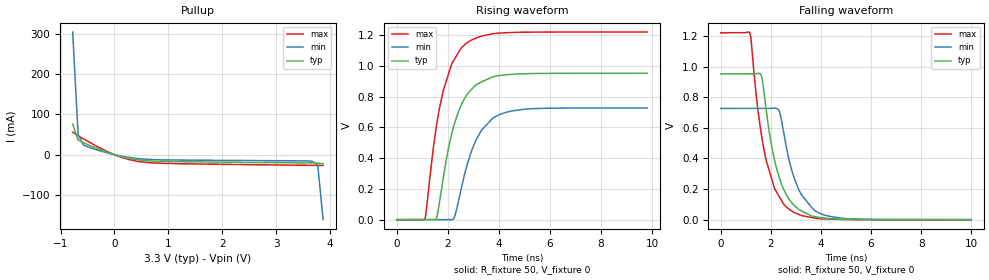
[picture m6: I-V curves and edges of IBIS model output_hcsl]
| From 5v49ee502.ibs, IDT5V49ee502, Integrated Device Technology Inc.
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[Model]   output_hcsl
Model_type   Open_source
Polarity   Non-Inverting
|   typ   min   max
C_comp   2pF   1.5pF   2.5pF
Vmeas = 0.475V
Rref = 50
Cref = 0
Vref = 0V
|   typ   min   max
[Voltage range]   3.3V   3.135V   3.465V
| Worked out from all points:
|   slope of the pullup table from 0 to 0.495 V, typ, clamps not added: 36.2 ohm
|   rising waveform, R_fixture 50, V_fixture 0: 20-80 % time 825ps typ, 869ps min, 802ps max; typ from 0 V to 0.952 V
|   falling waveform, R_fixture 50, V_fixture 0: 20-80 % time 756ps typ, 809ps min, 757ps max; typ from 0.952 V to 0 V
[Pullup]
|Voltage   I (typ)   I (min)   I (max)
|Note, modeling breaks down at 250mA and above.  This is well beyond the functional   |
|operating range of the device.  Should this scenario occur, catastrophic failure and   |
|possible damage to the device and/or board is of higher concern than the I-V curve   |
|behavior.  The IBIS checker will flag currents in excess of 10A with warnings.  Lines   |
|with currents in excess of 0.35 A have been commented out.  The points still remain|
|available to the user if the user desires to use them.   |
|-3.30000e+00   3.30638e+01   2.68010e+01   4.09657e+01
|-3.19898e+00   3.16603e+01   2.56927e+01   3.91797e+01
|-3.09796e+00   3.02576e+01   2.45850e+01   3.73944e+01
|-2.99694e+00   2.88557e+01   2.34780e+01   3.56099e+01
|-2.89592e+00   2.74545e+01   2.23718e+01   3.38263e+01
|-2.79490e+00   2.60544e+01   2.12664e+01   3.20438e+01
|-2.69388e+00   2.46552e+01   2.01619e+01   3.02623e+01
|-2.59286e+00   2.32572e+01   1.90584e+01   2.84820e+01
|-2.49184e+00   2.18605e+01   1.79561e+01   2.67032e+01
|-2.39082e+00   2.04653e+01   1.68551e+01   2.49259e+01
|-2.28980e+00   1.90717e+01   1.57554e+01   2.31504e+01
|-2.18878e+00   1.76800e+01   1.46575e+01   2.13771e+01
|-2.08776e+00   1.62905e+01   1.35614e+01   1.96061e+01
|-1.98673e+00   1.49036e+01   1.24675e+01   1.78381e+01
|-1.88571e+00   1.35198e+01   1.13762e+01   1.60736e+01
|-1.78469e+00   1.21397e+01   1.02880e+01   1.43133e+01
|-1.68367e+00   1.07642e+01   9.20353e+00   1.25584e+01
|-1.58265e+00   9.39447e+00   8.12370e+00   1.08104e+01
|-1.48163e+00   8.03224e+00   7.04975e+00   9.07171e+00
|-1.38061e+00   6.68011e+00   5.98351e+00   7.34597e+00
|-1.27959e+00   5.34234e+00   4.92772e+00   5.63973e+00
|-1.17857e+00   4.02639e+00   3.88695e+00   3.96580e+00
|-1.07755e+00   2.74730e+00   2.86935e+00   2.35494e+00
|-9.76531e-01   1.54173e+00   1.89160e+00   9.10722e-01
|-8.75510e-01   5.30047e-01   9.94813e-01   1.14991e-01
-774.5mV  75.97mA    304.6mA    55.9mA
-673.5mV  36.54mA    49.92mA    47.19mA
-572.4mV  29.57mA    23.79mA    39.18mA
-269.4mV  12.55mA    9.581mA    16.85mA
33.67mV   -1.332mA   -1.006mA   -1.807mA
235.7mV   -8.073mA   -6.115mA   -10.81mA
538.8mV   -14.28mA   -10.89mA   -18.63mA
1.246V    -17.55mA   -13.41mA   -22.54mA
3.67V     -20.48mA   -16.38mA   -26.54mA
3.771V    -20.93mA   -25.11mA   -26.7mA
3.872V    -22.81mA   -161.4mA   -27.04mA
| 3.97347e+00   -2.79466e-02   -1.04304e+00   -2.88374e-02
| 4.07449e+00   -6.78709e-02   -2.66934e+00   -3.44018e-02
| 4.17551e+00   -7.30752e-01   -4.58651e+00   -4.33487e-02
| 4.27653e+00   -2.68539e+00   -6.62766e+00   -5.68464e-02
| 4.37755e+00   -5.16352e+00   -8.73431e+00   -3.27836e-01
| 4.47857e+00   -7.82651e+00   -1.08809e+01   -2.58251e+00
| 4.57959e+00   -1.05777e+01   -1.30540e+01   -6.00804e+00
| 4.68061e+00   -1.33796e+01   -1.52462e+01   -9.74126e+00
| 4.78163e+00   -1.62143e+01   -1.74525e+01   -1.35998e+01
| 4.88265e+00   -1.90717e+01   -1.96699e+01   -1.75251e+01
| 4.98367e+00   -2.19459e+01   -2.18959e+01   -2.14915e+01
| 5.08469e+00   -2.48328e+01   -2.41291e+01   -2.54857e+01
| 5.18571e+00   -2.77298e+01   -2.63682e+01   -2.95000e+01
| 5.28673e+00   -3.06350e+01   -2.86123e+01   -3.35293e+01
| 5.38776e+00   -3.35469e+01   -3.08606e+01   -3.75704e+01
| 5.48878e+00   -3.64644e+01   -3.31126e+01   -4.16209e+01
| 5.58980e+00   -3.93867e+01   -3.53678e+01   -4.56791e+01
| 5.69082e+00   -4.23132e+01   -3.76258e+01   -4.97438e+01
| 5.79184e+00   -4.52432e+01   -3.98863e+01   -5.38139e+01
| 5.89286e+00   -4.81763e+01   -4.21491e+01   -5.78887e+01
| 5.99388e+00   -5.11123e+01   -4.44138e+01   -6.19676e+01
| 6.09490e+00   -5.40507e+01   -4.66804e+01   -6.60500e+01
| 6.19592e+00   -5.69914e+01   -4.89486e+01   -7.01355e+01
| 6.29694e+00   -5.99340e+01   -5.12183e+01   -7.42237e+01
| 6.39796e+00   -6.28785e+01   -5.34893e+01   -7.83145e+01
| 6.49898e+00   -6.58246e+01   -5.57616e+01   -8.24075e+01
| 6.60000e+00   -6.87722e+01   -5.80351e+01   -8.65025e+01
[Ramp]
|   typ   min   max
dV/dt_r   0.571/0.824n   0.435/0.868n   0.732/0.802n
dV/dt_f   0.573/0.755n   0.436/0.808n   0.735/0.757n
R_load =   50.0000
[Rising Waveform]
R_fixture = 50
V_fixture = 0   |Vcc_typ
V_fixture_min = 0 |Vcc_min
V_fixture_max = 0 |Vcc_max
C_fixture = 0.0p
| Time   typ   min   max
0s        193.5nV    161.3nV    244.3nV
1.101ns   171nV      160.8nV    5.079mV
1.551ns   6.706mV    153.6nV    604.4mV
1.807ns   255.1mV    387.4nV    829.7mV
2.027ns   465mV      -11.01uV   946.7mV
2.258ns   622.3mV    14.8mV     1.042V
2.742ns   809.7mV    348.2mV    1.148V
3.324ns   896.1mV    582.3mV    1.193V
4.256ns   941.6mV    696.6mV    1.215V
9.807ns   951.7mV    726.2mV    1.22V
[Falling Waveform]
R_fixture = 50
V_fixture = 0   |Vcc_typ
V_fixture_min = 0 |Vcc_min
V_fixture_max = 0 |Vcc_max
C_fixture = 0.0p
| Time   typ   min   max
0s        951.9mV    726.3mV    1.22V
1.156ns   951.9mV    726.3mV    1.22V
1.616ns   942.8mV    726.3mV    560.7mV
1.81ns    719.4mV    726.3mV    388.6mV
2.05ns    465.3mV    727mV      256.9mV
2.343ns   274.4mV    706mV      147.7mV
2.718ns   136.2mV    396.7mV    69.55mV
3.225ns   57.13mV    162.3mV    27.1mV
4.193ns   9.454mV    27.72mV    4.746mV
10ns      240.7uV    324uV      187.2uV
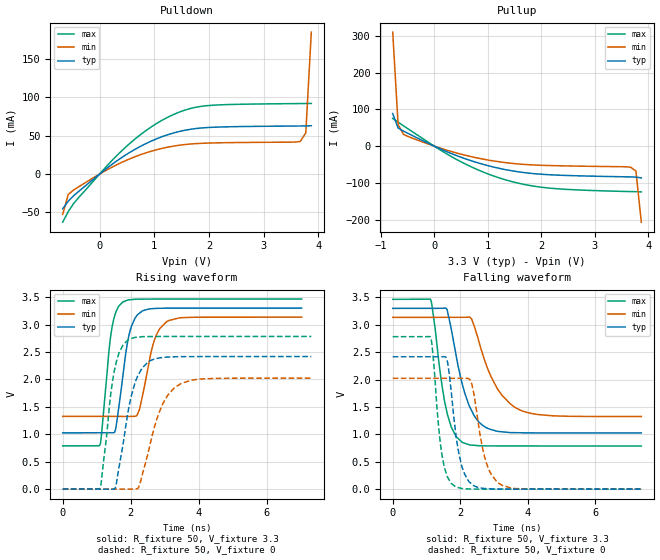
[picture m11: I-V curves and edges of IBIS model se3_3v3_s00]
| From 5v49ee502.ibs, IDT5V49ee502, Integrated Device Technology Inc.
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[Model]   se3_3v3_s00
Model_type   Output
Polarity   Non-Inverting
|   typ   min   max
C_comp   2pF   1.5pF   2.5pF
Vmeas = 1.65V
Rref = 50
Cref = 0
Vref = 1.65V
|   typ   min   max
[Voltage range]   3.3V   3.135V   3.465V
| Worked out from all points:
|   slope of the pulldown table from 0 to 0.495 V, typ, clamps not added: 19.3 ohm
|   slope of the pullup table from 0 to 0.495 V, typ, clamps not added: 16.5 ohm
|   rising waveform, R_fixture 50, V_fixture 3.3: 20-80 % time 316ps typ, 388ps min, 255ps max; typ from 1.03 V to 3.3 V
|   falling waveform, R_fixture 50, V_fixture 3.3: 20-80 % time 540ps typ, 760ps min, 382ps max; typ from 3.3 V to 1.03 V
|   rising waveform, R_fixture 50, V_fixture 0: 20-80 % time 443ps typ, 599ps min, 332ps max; typ from 0 V to 2.42 V
|   falling waveform, R_fixture 50, V_fixture 0: 20-80 % time 314ps typ, 381ps min, 254ps max; typ from 2.42 V to 0 V
[Pulldown]
|Voltage   I (typ)   I (min)   I (max)
|Note, modeling breaks down at 250mA and above.  This is well beyond the functional   |
|operating range of the device.  Should this scenario occur, catastrophic failure and   |
|possible damage to the device and/or board is of higher concern than the I-V curve   |
|behavior.  The IBIS checker will flag currents in excess of 10A with warnings.  Lines   |
|with currents in excess of 0.35 A have been commented out.  The points still remain|
|available to the user if the user desires to use them.   |
|-3.30000e+00   -6.87686e+01   -5.43171e+01   -9.32008e+01
|-3.19898e+00   -6.58203e+01   -5.20452e+01   -8.91014e+01
|-3.09796e+00   -6.28735e+01   -4.97746e+01   -8.50038e+01
|-2.99694e+00   -5.99283e+01   -4.75054e+01   -8.09081e+01
|-2.89592e+00   -5.69850e+01   -4.52379e+01   -7.68145e+01
|-2.79490e+00   -5.40436e+01   -4.29721e+01   -7.27232e+01
|-2.69388e+00   -5.11045e+01   -4.07082e+01   -6.86345e+01
|-2.59286e+00   -4.81679e+01   -3.84464e+01   -6.45487e+01
|-2.49184e+00   -4.52341e+01   -3.61871e+01   -6.04662e+01
|-2.39082e+00   -4.23034e+01   -3.39304e+01   -5.63874e+01
|-2.28980e+00   -3.93763e+01   -3.16768e+01   -5.23129e+01
|-2.18878e+00   -3.64533e+01   -2.94267e+01   -4.82433e+01
|-2.08776e+00   -3.35351e+01   -2.71807e+01   -4.41794e+01
|-1.98673e+00   -3.06226e+01   -2.49393e+01   -4.01225e+01
|-1.88571e+00   -2.77168e+01   -2.27035e+01   -3.60739e+01
|-1.78469e+00   -2.48192e+01   -2.04743e+01   -3.20355e+01
|-1.68367e+00   -2.19317e+01   -1.82533e+01   -2.80101e+01
|-1.58265e+00   -1.90571e+01   -1.60423e+01   -2.40013e+01
|-1.48163e+00   -1.61992e+01   -1.38443e+01   -2.00151e+01
|-1.38061e+00   -1.33643e+01   -1.16633e+01   -1.60610e+01
|-1.27959e+00   -1.05622e+01   -9.50583e+00   -1.21557e+01
|-1.17857e+00   -7.81131e+00   -7.38261e+00   -8.33341e+00
|-1.07755e+00   -5.14939e+00   -5.31366e+00   -4.68044e+00
|-9.76531e-01   -2.67462e+00   -3.34162e+00   -1.51483e+00
|-8.75510e-01   -7.31794e-01   -1.57851e+00   -1.44651e-01
|-7.74490e-01   -8.69816e-02   -3.68375e-01   -7.86452e-02
-673.5mV  -45.24mA   -52.43mA   -62.63mA
-572.4mV  -35.28mA   -26.51mA   -48.86mA
-471.4mV  -27.99mA   -20.59mA   -38.06mA
134.7mV   7.697mA    5.495mA    10.74mA
437.8mV   23.12mA    16.34mA    32.53mA
841.8mV   39.56mA    27.55mA    56.35mA
1.246V    51.27mA    35.11mA    74.04mA
1.65V     58.26mA    39.16mA    85.27mA
1.953V    60.57mA    40.35mA    89.06mA
3.67V     62.68mA    42.56mA    91.89mA
3.771V    62.76mA    53.73mA    91.95mA
3.872V    63.02mA    185mA      92.02mA
| 3.97347e+00   6.55596e-02   7.41772e-01   9.21553e-02
| 4.07449e+00   1.08647e-01   1.58873e+00   9.27153e-02
| 4.17551e+00   5.80278e-01   2.54520e+00   9.46081e-02
| 4.27653e+00   1.59944e+00   3.55162e+00   1.01817e-01
| 4.37755e+00   2.80760e+00   4.58567e+00   3.34469e-01
| 4.47857e+00   4.08805e+00   5.63705e+00   1.48880e+00
| 4.57959e+00   5.40493e+00   6.70024e+00   3.02301e+00
| 4.68061e+00   6.74346e+00   7.77197e+00   4.66528e+00
| 4.78163e+00   8.09625e+00   8.85014e+00   6.35488e+00
| 4.88265e+00   9.45914e+00   9.93338e+00   8.07065e+00
| 4.98367e+00   1.08295e+01   1.10207e+01   9.80297e+00
| 5.08469e+00   1.22057e+01   1.21113e+01   1.15467e+01
| 5.18571e+00   1.35865e+01   1.32047e+01   1.32987e+01
| 5.28673e+00   1.49710e+01   1.43004e+01   1.50570e+01
| 5.38776e+00   1.63587e+01   1.53982e+01   1.68204e+01
| 5.48878e+00   1.77491e+01   1.64978e+01   1.85878e+01
| 5.58980e+00   1.91417e+01   1.75989e+01   2.03586e+01
| 5.69082e+00   2.05363e+01   1.87014e+01   2.21323e+01
| 5.79184e+00   2.19327e+01   1.98051e+01   2.39084e+01
| 5.89286e+00   2.33306e+01   2.09099e+01   2.56866e+01
| 5.99388e+00   2.47298e+01   2.20158e+01   2.74666e+01
| 6.09490e+00   2.61303e+01   2.31225e+01   2.92482e+01
| 6.19592e+00   2.75319e+01   2.42301e+01   3.10313e+01
| 6.29694e+00   2.89346e+01   2.53384e+01   3.28157e+01
| 6.39796e+00   3.03381e+01   2.64475e+01   3.46012e+01
| 6.49898e+00   3.17425e+01   2.75572e+01   3.63877e+01
| 6.60000e+00   3.31476e+01   2.86675e+01   3.81752e+01
[Pullup]
|Voltage   I (typ)   I (min)   I (max)
|Note, modeling breaks down at 250mA and above.  This is well beyond the functional   |
|operating range of the device.  Should this scenario occur, catastrophic failure and   |
|possible damage to the device and/or board is of higher concern than the I-V curve   |
|behavior.  The IBIS checker will flag currents in excess of 10A with warnings.  Lines   |
|with currents in excess of 0.35 A have been commented out.  The points still remain|
|available to the user if the user desires to use them.   |
|-3.30000e+00   3.30662e+01   2.68026e+01   4.09695e+01
|-3.19898e+00   3.16627e+01   2.56942e+01   3.91833e+01
|-3.09796e+00   3.02599e+01   2.45865e+01   3.73979e+01
|-2.99694e+00   2.88578e+01   2.34795e+01   3.56133e+01
|-2.89592e+00   2.74566e+01   2.23732e+01   3.38296e+01
|-2.79490e+00   2.60564e+01   2.12677e+01   3.20468e+01
|-2.69388e+00   2.46571e+01   2.01632e+01   3.02652e+01
|-2.59286e+00   2.32591e+01   1.90597e+01   2.84848e+01
|-2.49184e+00   2.18623e+01   1.79573e+01   2.67058e+01
|-2.39082e+00   2.04670e+01   1.68562e+01   2.49284e+01
|-2.28980e+00   1.90733e+01   1.57565e+01   2.31528e+01
|-2.18878e+00   1.76815e+01   1.46585e+01   2.13793e+01
|-2.08776e+00   1.62920e+01   1.35624e+01   1.96083e+01
|-1.98673e+00   1.49050e+01   1.24685e+01   1.78401e+01
|-1.88571e+00   1.35211e+01   1.13771e+01   1.60755e+01
|-1.78469e+00   1.21410e+01   1.02889e+01   1.43151e+01
|-1.68367e+00   1.07654e+01   9.20440e+00   1.25601e+01
|-1.58265e+00   9.39567e+00   8.12456e+00   1.08121e+01
|-1.48163e+00   8.03343e+00   7.05061e+00   9.07334e+00
|-1.38061e+00   6.68134e+00   5.98439e+00   7.34764e+00
|-1.27959e+00   5.34365e+00   4.92866e+00   5.64154e+00
|-1.17857e+00   4.02789e+00   3.88799e+00   3.96799e+00
|-1.07755e+00   2.74922e+00   2.87060e+00   2.35810e+00
|-9.76531e-01   1.54469e+00   1.89327e+00   9.17282e-01
|-8.75510e-01   5.36267e-01   9.97483e-01   1.33294e-01
-774.5mV  88.48mA    310mA      75.29mA
-673.5mV  49mA       58.32mA    64.98mA
-572.4mV  40.75mA    31.76mA    55.15mA
-67.35mV  4.603mA    3.395mA    6.411mA
437.8mV   -26.87mA   -19.51mA   -37.82mA
841.8mV   -46.61mA   -33.39mA   -66.08mA
1.347V    -64.42mA   -45.25mA   -92.37mA
1.751V    -73.29mA   -50.54mA   -106.3mA
2.155V    -77.96mA   -52.94mA   -114.3mA
3.67V     -83.83mA   -57.37mA   -123.8mA
3.771V    -84.41mA   -67.8mA    -124.1mA
3.872V    -86.53mA   -207mA     -124.6mA
| 3.97347e+00   -9.23636e-02   -1.08741e+00   -1.26631e-01
| 4.07449e+00   -1.35075e-01   -2.71250e+00   -1.32720e-01
| 4.17551e+00   -7.98376e-01   -4.62912e+00   -1.42442e-01
| 4.27653e+00   -2.75140e+00   -6.66999e+00   -1.56925e-01
| 4.37755e+00   -5.22889e+00   -8.77650e+00   -4.29683e-01
| 4.47857e+00   -7.89161e+00   -1.09230e+01   -2.68260e+00
| 4.57959e+00   -1.06427e+01   -1.30961e+01   -6.10746e+00
| 4.68061e+00   -1.34446e+01   -1.52882e+01   -9.84047e+00
| 4.78163e+00   -1.62792e+01   -1.74945e+01   -1.36990e+01
| 4.88265e+00   -1.91366e+01   -1.97119e+01   -1.76242e+01
| 4.98367e+00   -2.20108e+01   -2.19380e+01   -2.15907e+01
| 5.08469e+00   -2.48978e+01   -2.41712e+01   -2.55849e+01
| 5.18571e+00   -2.77948e+01   -2.64103e+01   -2.95993e+01
| 5.28673e+00   -3.07000e+01   -2.86544e+01   -3.36287e+01
| 5.38776e+00   -3.36120e+01   -3.09027e+01   -3.76698e+01
| 5.48878e+00   -3.65296e+01   -3.31547e+01   -4.17205e+01
| 5.58980e+00   -3.94519e+01   -3.54100e+01   -4.57788e+01
| 5.69082e+00   -4.23784e+01   -3.76680e+01   -4.98436e+01
| 5.79184e+00   -4.53085e+01   -3.99286e+01   -5.39138e+01
| 5.89286e+00   -4.82418e+01   -4.21914e+01   -5.79887e+01
| 5.99388e+00   -5.11778e+01   -4.44562e+01   -6.20677e+01
| 6.09490e+00   -5.41163e+01   -4.67228e+01   -6.61502e+01
| 6.19592e+00   -5.70570e+01   -4.89910e+01   -7.02359e+01
| 6.29694e+00   -5.99998e+01   -5.12608e+01   -7.43243e+01
| 6.39796e+00   -6.29443e+01   -5.35319e+01   -7.84152e+01
| 6.49898e+00   -6.58905e+01   -5.58042e+01   -8.25083e+01
| 6.60000e+00   -6.88383e+01   -5.80778e+01   -8.66035e+01
[Ramp]
|   typ   min   max
dV/dt_r   1.364/0.316n   1.085/0.387n   1.606/0.254n
dV/dt_f   1.368/0.54n  1.089/0.76n   1.608/0.381n
R_load =   50.0000
[Rising Waveform]
R_fixture = 50
V_fixture = 3.3   |Vcc_typ
V_fixture_min = 3.135 |Vcc_min
V_fixture_max = 3.465 |Vcc_max
C_fixture = 0.0p
| Time   typ   min   max
0s        1.026V     1.326V     788.2mV
1.107ns   1.026V     1.326V     824.6mV
1.432ns   1.025V     1.326V     2.874V
1.568ns   1.124V     1.326V     3.235V
1.768ns   2.057V     1.326V     3.412V
1.942ns   2.786V     1.326V     3.451V
2.124ns   3.113V     1.328V     3.462V
2.72ns    3.294V     2.756V     3.465V
3.118ns   3.299V     3.074V     3.465V
7.03ns    3.3V       3.135V     3.465V
[Falling Waveform]
R_fixture = 50
V_fixture = 3.3   |Vcc_typ
V_fixture_min = 3.135 |Vcc_min
V_fixture_max = 3.465 |Vcc_max
C_fixture = 0.0p
| Time   typ   min   max
0s        3.3V       3.135V     3.465V
1.115ns   3.3V       3.135V     3.469V
1.461ns   3.301V     3.135V     1.88V
1.618ns   3.255V     3.135V     1.365V
2.065ns   1.905V     3.135V     852.3mV
2.334ns   1.435V     3.109V     804.2mV
2.6ns     1.196V     2.589V     792mV
3.1ns     1.056V     1.83V      788.9mV
3.61ns    1.031V     1.495V     788.4mV
7.359ns   1.026V     1.326V     788.3mV
[Rising Waveform]
R_fixture = 50
V_fixture = 0
C_fixture = 0.0p
| Time   typ   min   max
0s        2.408nV    9.927nV    273.5pV
1.107ns   -616.8nV   9.828nV    25.33mV
1.51ns    -666.9uV   -50.38nV   2.131V
1.654ns   385.6mV    -646nV     2.48V
1.937ns   1.461V     67.11uV    2.727V
2.231ns   2.088V     25.05mV    2.772V
2.469ns   2.293V     550mV      2.781V
2.946ns   2.4V       1.558V     2.783V
3.483ns   2.416V     1.926V     2.783V
7.315ns   2.417V     2.024V     2.783V
[Falling Waveform]
R_fixture = 50
V_fixture = 0
C_fixture = 0.0p
| Time   typ   min   max
0s        2.417V     2.024V     2.783V
1.115ns   2.417V     2.024V     2.78V
1.456ns   2.417V     2.024V     633.4mV
1.628ns   2.302V     2.024V     213.4mV
1.872ns   988.7mV    2.024V     38.94mV
2.047ns   413.3mV    2.024V     11.56mV
2.256ns   136.4mV    2.014V     2.805mV
2.763ns   9.529mV    497.2mV    298.2uV
3.237ns   1.214mV    70.87mV    174.9uV
7.357ns   82.08uV    149.8uV    45.03uV
